# lvds_rx_x3.lef -- GENERATED by package/make_package.py (T12) from results/layout/lvds_rx_x3.gds (sha256 892add3ba9d5678886b7c95fd525a1ce2fd3bd1663b6679324fd69c7b6b96f89): Magic lef write -hide + power
# straps as VDD / VSS pins + RX antenna areas through the secondary-ESD resistor.  Do not edit by hand.
VERSION 5.7 ;
  NOWIREEXTENSIONATPIN ON ;
DIVIDERCHAR "/" ;
BUSBITCHARS "[]" ;
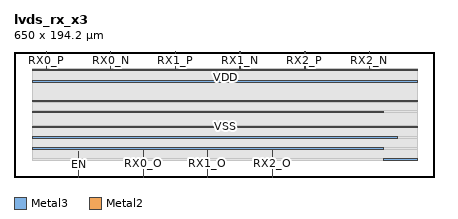
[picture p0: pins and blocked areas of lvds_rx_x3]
MACRO lvds_rx_x3
  CLASS BLOCK ;
  FOREIGN lvds_rx_x3 0 0 ;
  ORIGIN 0.000 0.000 ;
  SIZE 650.000 BY 194.200 ;
  SYMMETRY X Y ;
  PIN VDD
    DIRECTION INOUT ;
    USE POWER ;
    PORT
      LAYER Metal3 ;
        RECT 28.600 60.150 593.800 62.650 ;
        RECT 28.600 99.350 571.400 101.850 ;
        RECT 28.600 164.450 624.600 166.950 ;
    END
  END VDD
  PIN VSS
    DIRECTION INOUT ;
    USE GROUND ;
    PORT
      LAYER Metal3 ;
        RECT 28.600 42.650 571.400 45.150 ;
        RECT 28.600 76.250 624.600 78.750 ;
        RECT 28.600 116.150 624.600 118.650 ;
        RECT 28.600 146.950 624.600 149.450 ;
        RECT 571.400 25.850 624.600 28.350 ;
    END
  END VSS
  PIN RX0_P
    DIRECTION INOUT ;
    USE SIGNAL ;
    ANTENNADIFFAREA 80.0000 ;
    ANTENNAGATEAREA 65.9900 ;
    PORT
      LAYER Metal3 ;
        RECT 50.050 167.950 50.550 194.200 ;
    END
  END RX0_P
  PIN RX0_N
    DIRECTION INOUT ;
    USE SIGNAL ;
    ANTENNADIFFAREA 80.0000 ;
    ANTENNAGATEAREA 65.9900 ;
    PORT
      LAYER Metal3 ;
        RECT 149.450 167.950 149.950 194.200 ;
    END
  END RX0_N
  PIN RX1_P
    DIRECTION INOUT ;
    USE SIGNAL ;
    ANTENNADIFFAREA 80.0000 ;
    ANTENNAGATEAREA 65.9900 ;
    PORT
      LAYER Metal3 ;
        RECT 250.050 167.950 250.550 194.200 ;
    END
  END RX1_P
  PIN RX1_N
    DIRECTION INOUT ;
    USE SIGNAL ;
    ANTENNADIFFAREA 80.0000 ;
    ANTENNAGATEAREA 65.9900 ;
    PORT
      LAYER Metal3 ;
        RECT 349.450 167.950 349.950 194.200 ;
    END
  END RX1_N
  PIN RX2_P
    DIRECTION INOUT ;
    USE SIGNAL ;
    ANTENNADIFFAREA 80.0000 ;
    ANTENNAGATEAREA 65.9900 ;
    PORT
      LAYER Metal3 ;
        RECT 450.050 167.950 450.550 194.200 ;
    END
  END RX2_P
  PIN RX2_N
    DIRECTION INOUT ;
    USE SIGNAL ;
    ANTENNADIFFAREA 80.0000 ;
    ANTENNAGATEAREA 65.9900 ;
    PORT
      LAYER Metal3 ;
        RECT 549.450 167.950 549.950 194.200 ;
    END
  END RX2_N
  PIN EN
    DIRECTION INPUT ;
    USE SIGNAL ;
    ANTENNAGATEAREA 17.180000 ;
    PORT
      LAYER Metal2 ;
        RECT 99.860 0.000 100.140 39.910 ;
    END
  END EN
  PIN RX0_O
    DIRECTION OUTPUT ;
    USE SIGNAL ;
    ANTENNADIFFAREA 11.960000 ;
    PORT
      LAYER Metal2 ;
        RECT 199.860 0.000 200.140 40.610 ;
    END
  END RX0_O
  PIN RX1_O
    DIRECTION OUTPUT ;
    USE SIGNAL ;
    ANTENNADIFFAREA 11.960000 ;
    PORT
      LAYER Metal2 ;
        RECT 299.860 0.000 300.140 40.610 ;
    END
  END RX1_O
  PIN RX2_O
    DIRECTION OUTPUT ;
    USE SIGNAL ;
    ANTENNADIFFAREA 11.960000 ;
    PORT
      LAYER Metal2 ;
        RECT 399.860 0.000 400.140 40.610 ;
    END
  END RX2_O
  OBS
      LAYER Nwell ;
        RECT 32.800 30.650 624.200 162.650 ;
      LAYER Metal1 ;
        RECT 32.920 30.750 624.080 162.550 ;
      LAYER Metal2 ;
        RECT 29.200 40.910 623.120 168.350 ;
        RECT 29.200 40.210 199.560 40.910 ;
        RECT 29.200 25.850 99.560 40.210 ;
        RECT 100.440 25.850 199.560 40.210 ;
        RECT 200.440 25.850 299.560 40.910 ;
        RECT 300.440 25.850 399.560 40.910 ;
        RECT 400.440 25.850 623.120 40.910 ;
      LAYER Metal3 ;
        RECT 28.600 25.850 571.100 28.650 ;
        RECT 28.600 28.650 624.600 42.350 ;
        RECT 28.600 45.450 624.600 59.850 ;
        RECT 28.600 62.950 624.600 75.950 ;
        RECT 28.600 79.050 624.600 99.050 ;
        RECT 28.600 102.150 624.600 115.850 ;
        RECT 28.600 118.950 624.600 146.650 ;
        RECT 28.600 149.750 624.600 164.150 ;
        RECT 28.600 167.250 624.600 167.650 ;
        RECT 28.600 167.650 49.750 168.350 ;
        RECT 50.850 167.650 149.150 168.350 ;
        RECT 150.250 167.650 249.750 168.350 ;
        RECT 250.850 167.650 349.150 168.350 ;
        RECT 350.250 167.650 449.750 168.350 ;
        RECT 450.850 167.650 549.150 168.350 ;
        RECT 550.250 167.650 624.600 168.350 ;
        RECT 571.700 42.350 624.600 45.450 ;
        RECT 571.700 99.050 624.600 102.150 ;
        RECT 594.100 59.850 624.600 62.950 ;
  END
END lvds_rx_x3

END LIBRARY
